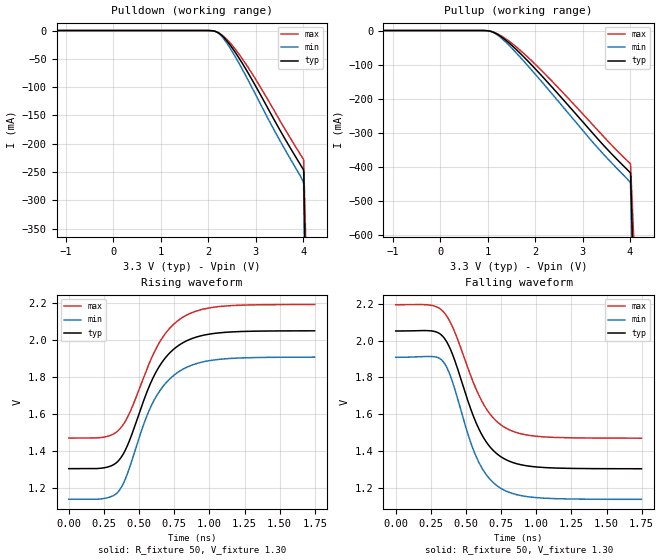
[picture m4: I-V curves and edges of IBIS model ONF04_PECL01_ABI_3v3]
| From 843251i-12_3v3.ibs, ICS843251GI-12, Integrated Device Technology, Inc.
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[Model] ONF04_PECL01_ABI_3v3
Model_type   Output_ECL
Polarity   Non-Inverting
|   typ   min   max
C_comp   2pF   1.5pF   2.5pF
Vmeas = 1.645V
Rref = 50
Cref = 0
Vref = 1.3V
|   typ   min   max
[Voltage range]   3.3V   3.135V   3.465V
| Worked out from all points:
|   rising waveform, R_fixture 50, V_fixture 1.30: 20-80 % time 253ps typ, 251ps min, 262ps max; typ from 1.3 V to 2.05 V
|   falling waveform, R_fixture 50, V_fixture 1.30: 20-80 % time 225ps typ, 213ps min, 239ps max; typ from 2.05 V to 1.3 V
[Pulldown]
|Voltage   I (typ)   I (min)   I (max)
-3.3V     8.435pA    8.27pA     10.14pA
1.978V    -30uA      -12.55uA   -49.61uA
2.176V    -2.399mA   -2.395mA   -2.347mA
2.274V    -7.941mA   -9.392mA   -6.987mA
2.422V    -21.5mA    -26.18mA   -18.35mA
2.767V    -64.88mA   -76.39mA   -56.15mA
3.014V    -100.6mA   -115.8mA   -88.36mA
3.359V    -153.3mA   -171.4mA   -137.1mA
3.951V    -238.3mA   -258.5mA   -220.1mA
4.01V     -246.7mA   -269.8mA   -228mA
4.528V    -2.674A    -3.924A    -1.877A
6.6V      -15.69A    -20.55A    -12.73A
[Pullup]
|Voltage   I (typ)   I (min)   I (max)
-3.3V     8.435pA    8.27pA     10.14pA
893.4mV   -58.67uA   -23.73uA   -91.59uA
1.041V    -1.686mA   -1.459mA   -1.72mA
1.14V     -6.43mA    -7.219mA   -5.711mA
1.288V    -18.8mA    -22.48mA   -16.03mA
1.485V    -40.9mA    -48.6mA    -34.97mA
1.978V    -108.8mA   -124.3mA   -95.74mA
2.521V    -191.6mA   -212.9mA   -172.6mA
3.26V     -308.3mA   -334.6mA   -283.3mA
4.01V     -417.2mA   -447.3mA   -390.8mA
4.528V    -2.844A    -4.101A    -2.04A
6.6V      -15.79A    -20.6A     -12.84A
[Ramp]
|   typ   min   max
dV/dt_r   0.599/0.406n   0.618/0.403n   0.58/0.417n
dV/dt_f   0.601/0.357n   0.621/0.339n   0.581/0.376n
R_load =   50.0000
[Rising Waveform]
R_fixture = 50
V_fixture = 1.30   | VCC_typ - 2V
V_fixture_max = 1.465   | VCC_max - 2V
V_fixture_min = 1.135   | VCC_min - 2V
C_fixture = 0.0p
| Time   typ   min   max
0s        1.303V     1.136V     1.469V
245.2ps   1.306V     1.14V      1.473V
352.1ps   1.345V     1.177V     1.51V
432.7ps   1.457V     1.31V      1.606V
532.5ps   1.672V     1.544V     1.8V
600.9ps   1.799V     1.666V     1.924V
693.7ps   1.911V     1.771V     2.044V
804.1ps   1.983V     1.84V      2.122V
1.077ns   2.041V     1.897V     2.184V
1.748ns   2.052V     1.908V     2.195V
[Falling Waveform]
R_fixture = 50
V_fixture = 1.30   | VCC_typ - 2V
V_fixture_max = 1.465   | VCC_max - 2V
V_fixture_min = 1.135   | VCC_min - 2V
C_fixture = 0.0p
| Time   typ   min   max
0s        2.052V     1.909V     2.195V
243.5ps   2.053V     1.913V     2.193V
338.1ps   2.02V      1.885V     2.157V
415.2ps   1.903V     1.749V     2.055V
516.8ps   1.665V     1.484V     1.843V
579.8ps   1.539V     1.356V     1.722V
658.7ps   1.433V     1.256V     1.613V
753.3ps   1.365V     1.194V     1.539V
1.011ns   1.312V     1.145V     1.478V
1.748ns   1.303V     1.136V     1.469V
